One B-rep face of a CAD part: STEP entity #1697.
In plain terms, the planar face has unit normal (-1, 0, 0).
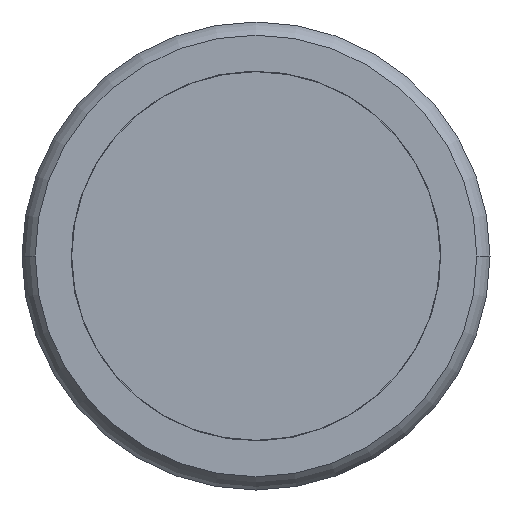
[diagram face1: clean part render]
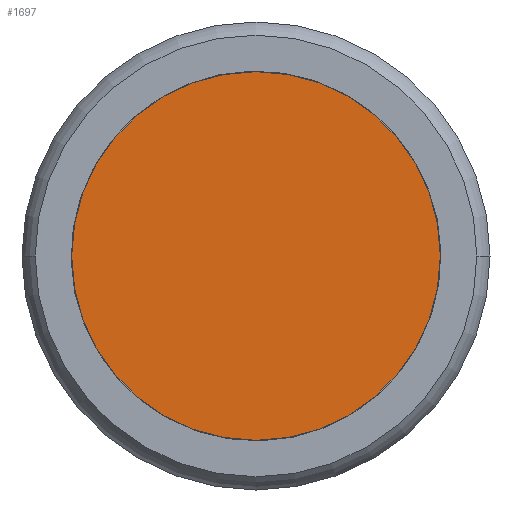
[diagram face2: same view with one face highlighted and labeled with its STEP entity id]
Its self-contained STEP definition (entity closure, numbers rounded to 3 decimals):
#1697 = ADVANCED_FACE ( 'NONE', ( #4813 ), #4820, .F. ) ;
#1819 = EDGE_CURVE ( 'NONE', #2727, #2714, #5759, .T. ) ;
#2714 = VERTEX_POINT ( 'NONE', #8019 ) ;
#2727 = VERTEX_POINT ( 'NONE', #7940 ) ;
#4784 = DIRECTION ( 'NONE',  ( 0., 1., 0. ) ) ;
#4786 = DIRECTION ( 'NONE',  ( 1., 0., 0. ) ) ;
#4813 = FACE_OUTER_BOUND ( 'NONE', #5715, .T. ) ;
#4820 = PLANE ( 'NONE',  #5319 ) ;
#4827 = CARTESIAN_POINT ( 'NONE',  ( 0.374, 1.735, -10. ) ) ;
#5319 = AXIS2_PLACEMENT_3D ( 'NONE', #4827, #4786, #4784 ) ;
#5715 = EDGE_LOOP ( 'NONE', ( #5792, #5814 ) ) ;
#5759 = CIRCLE ( 'NONE', #5778, 1.58 ) ;
#5778 = AXIS2_PLACEMENT_3D ( 'NONE', #7545, #7525, #7552 ) ;
#5792 = ORIENTED_EDGE ( 'NONE', *, *, #8308, .F. ) ;
#5814 = ORIENTED_EDGE ( 'NONE', *, *, #1819, .F. ) ;
#7525 = DIRECTION ( 'NONE',  ( 1., 0., 0. ) ) ;
#7545 = CARTESIAN_POINT ( 'NONE',  ( 0.374, 0., 0. ) ) ;
#7552 = DIRECTION ( 'NONE',  ( 0., 1., 0. ) ) ;
#7940 = CARTESIAN_POINT ( 'NONE',  ( 0.374, 0., -1.58 ) ) ;
#8019 = CARTESIAN_POINT ( 'NONE',  ( 0.374, 0., 1.58 ) ) ;
#8308 = EDGE_CURVE ( 'NONE', #2714, #2727, #11148, .T. ) ;
#10842 = DIRECTION ( 'NONE',  ( 1., 0., 0. ) ) ;
#10851 = CARTESIAN_POINT ( 'NONE',  ( 0.374, 0., 0. ) ) ;
#10864 = DIRECTION ( 'NONE',  ( 0., 1., 0. ) ) ;
#11140 = AXIS2_PLACEMENT_3D ( 'NONE', #10851, #10842, #10864 ) ;
#11148 = CIRCLE ( 'NONE', #11140, 1.58 ) ;
